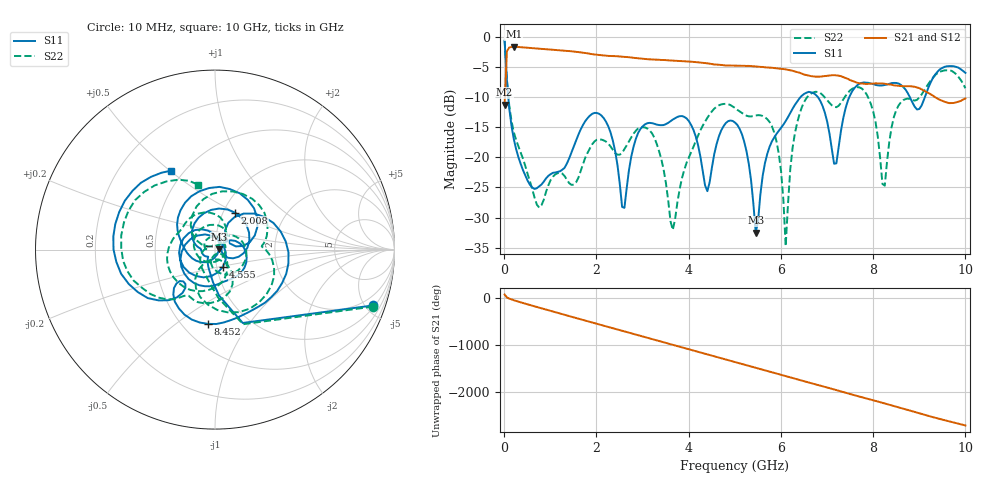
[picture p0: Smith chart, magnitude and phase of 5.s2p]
!Agilent Technologies,N5230C,MY49000813,A.09.42.22
!Agilent N5230C: A.09.42.22
!Date: Friday, August 21, 2026 19:36:31
!Correction: S11(Full 2 Port(1,2))
!S21(Full 2 Port(1,2))
!S12(Full 2 Port(1,2))
!S22(Full 2 Port(1,2))
!S2P File: Measurements: S11, S21, S12, S22:
# Hz S  dB  R 50
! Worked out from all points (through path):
!   201 points, 10 MHz to 10 GHz, reference 50 ohm
!   highest |S21| = -1.62 dB at 209.8 MHz (marker M1); lowest = -11.2 dB at 10 MHz (marker M2)
!   lowest |S11| = -32.5 dB at 5.455 GHz (marker M3), VSWR 1.05, Z = 52.4 + j0.179 ohm
!   |S11| at or under -10 dB: 90.42 MHz to 6.424 GHz (6.334 GHz wide, 194 % of centre); 6.805 GHz to 7.483 GHz (678.7 MHz wide, 9.5 % of centre); 8.796 GHz to 9.12 GHz (324 MHz wide, 3.62 % of centre)
!   |S22| runs from -34.7 to -0.6 dB; largest |S21 - S12| = 0.0031
!   S11 on the Smith chart (normalised r, x): 10 MHz: 1.18, -5.57; 2.008 GHz: 1.14, +0.49; 4.555 GHz: 1.07, -0.21; 8.452 GHz: 0.66, -0.66; 10 GHz: 0.43, +0.50
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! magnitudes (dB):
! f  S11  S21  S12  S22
! 10 MHz  -0.6  -11.2  -11.2  -0.6
! 209.8 MHz  -17.0  -1.6  -1.6  -15.8
! 759.2 MHz  -24.8  -1.9  -1.9  -28.3
! 1.708 GHz  -14.6  -2.6  -2.6  -21.1
! 2.008 GHz  -12.6  -2.9  -3.0  -17.1
! 2.607 GHz  -28.4  -3.3  -3.3  -18.6
! 3.357 GHz  -14.6  -3.8  -3.8  -18.9
! 3.656 GHz  -13.7  -3.9  -3.9  -32.1
! 4.406 GHz  -25.6  -4.4  -4.4  -13.4
! 4.555 GHz  -19.4  -4.6  -4.6  -11.9
! 5.005 GHz  -14.2  -4.8  -4.8  -11.8
! 5.455 GHz  -32.5  -4.9  -4.9  -13.0
! 5.904 GHz  -16.1  -5.2  -5.2  -17.3
! 6.104 GHz  -14.0  -5.4  -5.4  -34.7
! 6.304 GHz  -11.3  -5.7  -5.7  -16.0
! 6.703 GHz  -9.3  -6.5  -6.5  -9.2
! 7.153 GHz  -21.0  -6.3  -6.3  -11.6
! 7.852 GHz  -7.6  -7.8  -7.8  -9.4
! 8.252 GHz  -8.0  -7.8  -7.7  -24.7
! 8.352 GHz  -7.8  -7.9  -7.9  -17.3
! 8.452 GHz  -7.6  -8.0  -8.0  -13.2
! 10 GHz  -6.0  -10.2  -10.2  -8.5
